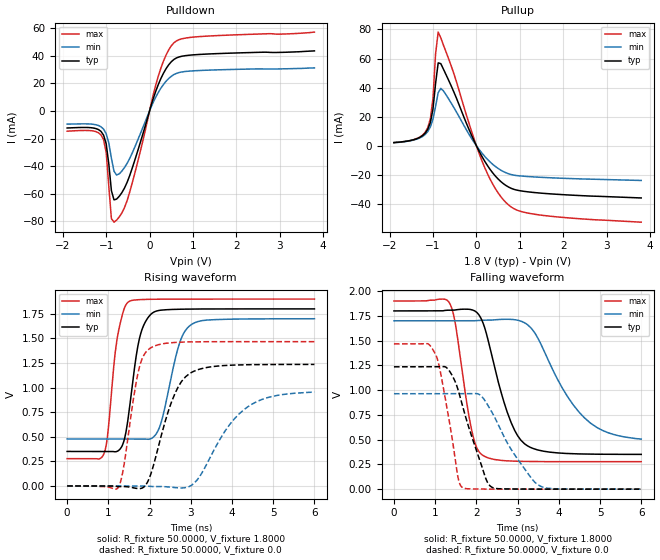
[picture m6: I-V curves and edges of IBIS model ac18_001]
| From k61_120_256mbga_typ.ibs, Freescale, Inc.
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|   Model ac18_001
[Model]  ac18_001
Model_type Output
Polarity   Non-Inverting
Enable   Active-High
Vmeas =  0.9000V
Cref =   5.0000pF
Rref =   50.0000
C_comp   2.8000pF   2.5000pF   3.3000pF
[Temperature Range]   25.0000   0.1250k   -40.0000
[Voltage Range]   1.8000V   1.7000V   1.9000V
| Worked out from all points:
|   slope of the pulldown table from 0 to 0.27 V, typ, clamps not added: 11.2 ohm
|   slope of the pullup table from 0 to 0.27 V, typ, clamps not added: 18.8 ohm
|   rising waveform, R_fixture 50.0000, V_fixture 1.8000: 20-80 % time 297ps typ, 401ps min, 243ps max; typ from 0.351 V to 1.8 V
|   rising waveform, R_fixture 50.0000, V_fixture 0.0: 20-80 % time 552ps typ, 907ps min, 324ps max; typ from 0 V to 1.24 V
|   falling waveform, R_fixture 50.0000, V_fixture 1.8000: 20-80 % time 596ps typ, 998ps min, 356ps max; typ from 1.8 V to 0.351 V
|   falling waveform, R_fixture 50.0000, V_fixture 0.0: 20-80 % time 552ps typ, 805ps min, 357ps max; typ from 1.24 V to 0 V
[Pulldown]
|Voltage   I(typ)   I(min)   I(max)
-1.9V     -12.39mA   -9.603mA   -14.7mA
-1.24V    -12.78mA   -10.03mA   -14.98mA
-1.06V    -17.59mA   -13.19mA   -20.88mA
-1V       -23.85mA   -16.51mA   -30.08mA
-880mV    -57.69mA   -34.18mA   -77.95mA
-820mV    -64.39mA   -43.65mA   -80.55mA
-700mV    -61.85mA   -45.6mA    -76.81mA
-520mV    -51.88mA   -38.09mA   -65.13mA
200mV     18.96mA    13.28mA    25.03mA
380mV     30.52mA    21.42mA    40.4mA
560mV     37.18mA    26.25mA    49.21mA
3.8V      43.4mA     31.1mA     57mA
[Pullup]
|Voltage   I(typ)   I(min)   I(max)
-1.9V     2.1mA      2.1mA      2.2mA
-1.36V    4.94mA     4.66mA     5.08mA
-1.12V    11.3mA     9.73mA     12.41mA
-1.06V    15.99mA    12.93mA    18.54mA
-1V       25.26mA    18.31mA    32.65mA
-940mV    42.87mA    27.06mA    63.32mA
-880mV    57.01mA    36.48mA    78.2mA
-760mV    52.75mA    37.76mA    69.31mA
140mV     -8.031mA   -5.52mA    -11.29mA
680mV     -27.37mA   -18.62mA   -39.09mA
1.4V      -32.43mA   -21.63mA   -47.45mA
3.8V      -35.98mA   -23.94mA   -52.67mA
[Ramp]
| variable   typ   min   max
dV/dt_r  0.7414/0.5524n   0.5724/0.9071n   0.8802/0.3244n
dV/dt_f  0.8693/0.5960n   0.7168/0.9978n   0.9734/0.3560n
R_load = 50.0000
[Rising Waveform]
R_fixture= 50.0000
V_fixture= 1.8000
V_fixture_min= 1.7000
V_fixture_max= 1.9000
|time   V(typ)   V(min)   V(max)
0s        350.9mV    477.7mV    277.6mV
902ps     350.9mV    477.7mV    337.4mV
1.21ns    351.3mV    477.7mV    1.49V
1.368ns   443.5mV    477.7mV    1.782V
1.498ns   743.7mV    477.7mV    1.875V
1.772ns   1.529V     478mV      1.895V
2.11ns    1.769V     503.5mV    1.898V
2.731ns   1.797V     1.456V     1.9V
2.996ns   1.798V     1.636V     1.9V
6ns       1.8V       1.7V       1.9V
[Rising Waveform]
R_fixture= 50.0000
V_fixture= 0.0
|time   V(typ)   V(min)   V(max)
0s        2.838nV    312.1nV    728.3pV
1.244ns   -6.3mV     729.9nV    -12.57mV
1.364ns   -5.753mV   306.7nV    173.6mV
1.745ns   -26.8mV    98.4uV     1.195V
2.052ns   148.3mV    -5.631mV   1.41V
2.537ns   859.2mV    -12.92mV   1.457V
2.947ns   1.136V     -8.28mV    1.464V
4.277ns   1.232V     771.2mV    1.467V
4.973ns   1.235V     910mV      1.467V
6ns       1.236V     954mV      1.467V
[Falling Waveform]
R_fixture= 50.0000
V_fixture= 1.8000
V_fixture_min= 1.7000
V_fixture_max= 1.9000
|time   V(typ)   V(min)   V(max)
0s        1.8V       1.7V       1.9V
1.344ns   1.807V     1.7V       1.883V
1.497ns   1.81V      1.7V       1.655V
1.907ns   1.809V     1.7V       556.3mV
2.165ns   1.675V     1.706V     339.2mV
2.746ns   780.4mV    1.716V     285.9mV
3.167ns   458.7mV    1.681V     279.9mV
3.434ns   402.7mV    1.567V     278.6mV
4.621ns   354.8mV    720.6mV    277.7mV
6ns       351.2mV    505.3mV    277.6mV
[Falling Waveform]
R_fixture= 50.0000
V_fixture= 0.0
|time   V(typ)   V(min)   V(max)
0s        1.236V     963.7mV    1.467V
813.7ps   1.236V     963.7mV    1.469V
1.008ns   1.236V     963.7mV    1.365V
1.343ns   1.195V     963.7mV    688mV
1.557ns   1.002V     963.7mV    113.1mV
1.671ns   830.9mV    963.7mV    14.3mV
2.088ns   287mV      951.8mV    1.404mV
2.395ns   15.56mV    763.8mV    542.2uV
3.517ns   405.5uV    38.29mV    16.24uV
6ns       1.818uV    122uV      -80.32nV
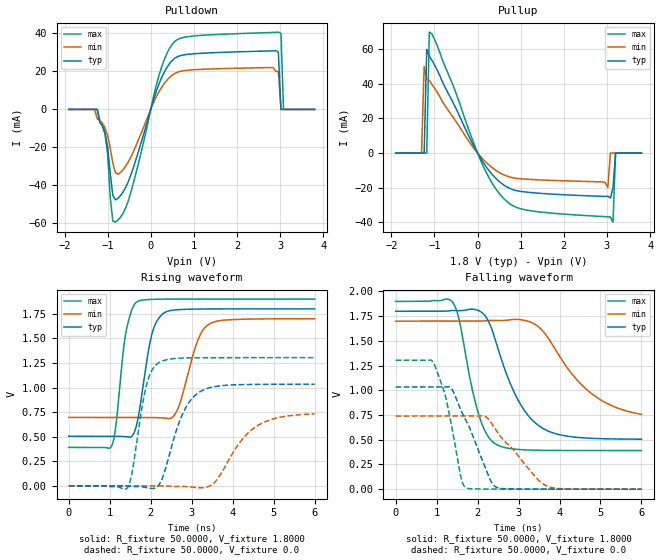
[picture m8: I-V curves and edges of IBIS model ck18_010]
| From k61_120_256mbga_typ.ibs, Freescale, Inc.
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|   Model ck18_010
[Model]  ck18_010
Model_type Output
Polarity   Non-Inverting
Enable   Active-High
Vmeas =  0.9000V
Cref =   5.0000pF
Rref =   50.0000
C_comp   2.8000pF   2.5000pF   3.3000pF
[Temperature Range]   25.0000   0.1250k   -40.0000
[Voltage Range]   1.8000V   1.7000V   1.9000V
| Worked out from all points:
|   slope of the pulldown table from 0 to 0.27 V, typ, clamps not added: 15.4 ohm
|   slope of the pullup table from 0 to 0.27 V, typ, clamps not added: 26.2 ohm
|   rising waveform, R_fixture 50.0000, V_fixture 1.8000: 20-80 % time 304ps typ, 414ps min, 240ps max; typ from 0.504 V to 1.8 V
|   rising waveform, R_fixture 50.0000, V_fixture 0.0: 20-80 % time 518ps typ, 765ps min, 316ps max; typ from 0 V to 1.03 V
|   falling waveform, R_fixture 50.0000, V_fixture 1.8000: 20-80 % time 789ps typ, 1.1ns min, 470ps max; typ from 1.8 V to 0.505 V
|   falling waveform, R_fixture 50.0000, V_fixture 0.0: 20-80 % time 632ps typ, 906ps min, 390ps max; typ from 1.03 V to 0 V
[Pulldown]
|Voltage   I(typ)   I(min)   I(max)
-1.9V     0A         0A         0A
-1.24V    0A         -5mA       0A
-1.06V    -12.26mA   -9.75mA    -13.08mA
-880mV    -45.16mA   -28.29mA   -58.8mA
-820mV    -47.6mA    -33.26mA   -59.37mA
-460mV    -34.43mA   -25.08mA   -43.58mA
260mV     17.1mA     11.87mA    22.81mA
620mV     27.74mA    19.59mA    36.79mA
2.96V     30mA       20mA       40.7mA
3.02V     0A         0A         40mA
3.08V     0A         0A         0A
3.8V      0A         0A         0A
[Pullup]
|Voltage   I(typ)   I(min)   I(max)
-1.9V     0A         0A         0A
-1.3V     0A         0A         0A
-1.24V    0A         50mA       0A
-1.18V    60mA       43mA       0A
-1.12V    56mA       42mA       70mA
140mV     -5.775mA   -3.963mA   -8.136mA
800mV     -21mA      -14.21mA   -30.2mA
3.02V     -25mA      -20mA      -36.9mA
3.08V     -26mA      0A         -37mA
3.14V     -20mA      0A         -40mA
3.2V      0A         0A         0A
3.8V      0A         0A         0A
[Ramp]
| variable   typ   min   max
dV/dt_r  0.6201/0.5176n   0.4393/0.7629n   0.7822/0.3155n
dV/dt_f  0.7768/0.7888n   0.5661/1.0989n   0.9056/0.4703n
R_load = 50.0000
[Rising Waveform]
R_fixture= 50.0000
V_fixture= 1.8000
V_fixture_min= 1.7000
V_fixture_max= 1.9000
|time   V(typ)   V(min)   V(max)
0s        504.3mV    695.5mV    390.7mV
1.053ns   504.4mV    695.5mV    413.2mV
1.39ns    501.2mV    695.5mV    1.551V
1.663ns   631.2mV    695.5mV    1.872V
2.022ns   1.532V     695.5mV    1.897V
2.319ns   1.757V     690.8mV    1.899V
2.631ns   1.791V     756.2mV    1.9V
3.134ns   1.798V     1.463V     1.9V
3.407ns   1.799V     1.64V      1.9V
6ns       1.8V       1.7V       1.9V
[Rising Waveform]
R_fixture= 50.0000
V_fixture= 0.0
|time   V(typ)   V(min)   V(max)
0s        4.987nV    391nV      2.102nV
1.434ns   -1.187mV   550.7nV    -19.32mV
1.547ns   -8.89mV    -1.382uV   140.9mV
1.897ns   -18.33mV   151.2uV    1.023V
2.222ns   23.63mV    248.5uV    1.258V
2.749ns   703.7mV    -6.341mV   1.299V
3.183ns   952.1mV    -19.63mV   1.303V
3.559ns   1.009V     33.93mV    1.303V
4.643ns   1.032V     621.2mV    1.304V
6ns       1.034V     732.1mV    1.304V
[Falling Waveform]
R_fixture= 50.0000
V_fixture= 1.8000
V_fixture_min= 1.7000
V_fixture_max= 1.9000
|time   V(typ)   V(min)   V(max)
0s        1.8V       1.7V       1.9V
1.401ns   1.808V     1.7V       1.884V
1.549ns   1.806V     1.7V       1.716V
2.02ns    1.808V     1.7V       765.4mV
2.246ns   1.714V     1.706V     539.9mV
2.437ns   1.504V     1.706V     457.3mV
2.965ns   919.8mV    1.718V     402.7mV
3.528ns   631.9mV    1.628V     393.1mV
4.65ns    517.3mV    1.013V     390.8mV
6ns       505.4mV    756.5mV    390.7mV
[Falling Waveform]
R_fixture= 50.0000
V_fixture= 0.0
|time   V(typ)   V(min)   V(max)
0s        1.034V     739.7mV    1.304V
926.6ps   1.034V     739.7mV    1.274V
1.191ns   1.034V     739.7mV    980.9mV
1.35ns    1.023V     739.7mV    670.8mV
1.601ns   790.1mV    739.7mV    106mV
1.727ns   687.2mV    739.7mV    12.69mV
2.183ns   220.8mV    737mV      1.246mV
2.481ns   15.45mV    577.3mV    483.1uV
3.71ns    322.2uV    28.09mV    15.67uV
6ns       4.302uV    159uV      344.8nV
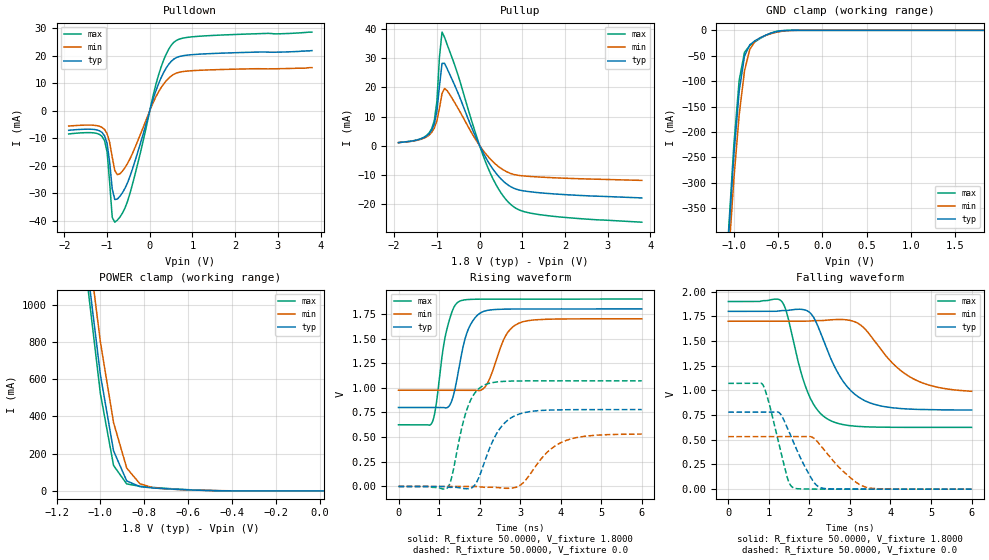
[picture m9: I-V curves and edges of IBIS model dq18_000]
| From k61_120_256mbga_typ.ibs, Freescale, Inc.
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|   Model dq18_000
[Model]  dq18_000
Model_type 3-state
Polarity   Non-Inverting
Enable   Active-High
Vmeas =  0.9000V
Cref =   5.0000pF
Rref =   50.0000
C_comp   2.8000pF   2.5000pF   3.3000pF
[Temperature Range]   25.0000   0.1250k   -40.0000
[Voltage Range]   1.8000V   1.7000V   1.9000V
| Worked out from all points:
|   slope of the pulldown table from 0 to 0.27 V, typ, clamps not added: 22.3 ohm
|   slope of the pullup table from 0 to 0.27 V, typ, clamps not added: 37.5 ohm
|   GND clamp passes 1 mA (typ) near -0.46 V on its own axis
|   POWER clamp passes 1 mA (typ) near -0.45 V on its own axis
|   rising waveform, R_fixture 50.0000, V_fixture 1.8000: 20-80 % time 328ps typ, 407ps min, 280ps max; typ from 0.801 V to 1.8 V
|   rising waveform, R_fixture 50.0000, V_fixture 0.0: 20-80 % time 529ps typ, 702ps min, 383ps max; typ from 0 V to 0.779 V
|   falling waveform, R_fixture 50.0000, V_fixture 1.8000: 20-80 % time 754ps typ, 996ps min, 547ps max; typ from 1.8 V to 0.801 V
|   falling waveform, R_fixture 50.0000, V_fixture 0.0: 20-80 % time 531ps typ, 730ps min, 379ps max; typ from 0.779 V to 0 V
[Pulldown]
|Voltage   I(typ)   I(min)   I(max)
-1.9V     -7.125mA   -5.577mA   -8.446mA
-1.3V     -6.824mA   -5.306mA   -8.077mA
-1.06V    -9.108mA   -6.813mA   -10.88mA
-1V       -11.95mA   -8.349mA   -14.97mA
-880mV    -28.41mA   -16.83mA   -38.71mA
-820mV    -32.23mA   -21.69mA   -40.45mA
-700mV    -31.06mA   -22.87mA   -38.6mA
-520mV    -26.09mA   -19.11mA   -32.8mA
200mV     9.554mA    6.678mA    12.65mA
380mV     15.35mA    10.75mA    20.37mA
560mV     18.67mA    13.17mA    24.75mA
3.8V      21.8mA     15.6mA     28.5mA
[Pullup]
|Voltage   I(typ)   I(min)   I(max)
-1.9V     1mA        1mA        1mA
-1.36V    2.37mA     2.22mA     2.46mA
-1.12V    5.32mA     4.56mA     5.88mA
-1.06V    7.48mA     6.03mA     8.69mA
-1V       11.81mA    8.57mA     15.23mA
-940mV    20.56mA    12.89mA    30.55mA
-880mV    28.3mA     17.89mA    39.08mA
-760mV    26.45mA    18.92mA    34.76mA
140mV     -4.031mA   -2.77mA    -5.668mA
680mV     -13.73mA   -9.341mA   -19.61mA
1.4V      -16.26mA   -10.85mA   -23.79mA
3.8V      -18.04mA   -12.01mA   -26.41mA
[GND_clamp]
|Voltage   I(typ)   I(min)   I(max)
-1.9V     -3.326A    -3.292A    -3.364A
-1.06V    -406.5mA   -447.4mA   -394.6mA
-1V       -245.1mA   -292.9mA   -225.5mA
-940mV    -119.4mA   -166.1mA   -98.22mA
-880mV    -50.5mA    -79.89mA   -43.13mA
-820mV    -28.4mA    -37.26mA   -29.9mA
-760mV    -20.29mA   -21.31mA   -22.38mA
-700mV    -14.5mA    -14.44mA   -15.67mA
-580mV    -5.551mA   -6.474mA   -5.066mA
-460mV    -1.018mA   -1.866mA   -602.3uA
-220mV    -979.5nA   -15.35uA   -59.46nA
1.82V     915.2pA    951.9nA    210.6pA
[POWER_clamp]
|Voltage   I(typ)   I(min)   I(max)
-1.9V     11.94A     11.89A     12.02A
-1.06V    1.204A     1.363A     1.122A
-1V       623.7mA    800mA      522.5mA
-940mV    215.1mA    367.1mA    136.6mA
-880mV    53.67mA    122.9mA    37.6mA
-820mV    23.13mA    38.48mA    24.96mA
-760mV    15.75mA    17.21mA    18.82mA
-640mV    7.758mA    7.284mA    9.105mA
-460mV    1.139mA    1.585mA    966.7uA
20mV      398.7pA    26.73nA    225pA
[Ramp]
| variable   typ   min   max
dV/dt_r  0.4676/0.5284n   0.3184/0.7023n   0.6427/0.3825n
dV/dt_f  0.5993/0.7541n   0.4255/0.9960n   0.7648/0.5470n
R_load = 50.0000
[Rising Waveform]
R_fixture= 50.0000
V_fixture= 1.8000
V_fixture_min= 1.7000
V_fixture_max= 1.9000
|time   V(typ)   V(min)   V(max)
0s        800.8mV    975.9mV    625.4mV
832.1ps   800.7mV    975.9mV    650.5mV
1.172ns   796.5mV    975.9mV    1.558V
1.322ns   877.7mV    975.9mV    1.775V
1.494ns   1.205V     975.9mV    1.876V
1.744ns   1.615V     976.1mV    1.896V
2.131ns   1.779V     1.008V     1.899V
2.62ns    1.798V     1.511V     1.9V
2.958ns   1.799V     1.653V     1.9V
6ns       1.8V       1.7V       1.9V
[Rising Waveform]
R_fixture= 50.0000
V_fixture= 0.0
|time   V(typ)   V(min)   V(max)
0s        8.256nV    861nV      2.296nV
1.216ns   -7.012mV   1.177uV    -10.98mV
1.676ns   -23.7mV    -4.494uV   768mV
1.892ns   19.47mV    69.68uV    952.6mV
2.112ns   236.5mV    -9.001mV   1.027V
2.478ns   574.3mV    -12.42mV   1.062V
2.966ns   732.3mV    3.157mV    1.07V
3.67ns    773.7mV    347.8mV    1.071V
4.109ns   777.9mV    462.5mV    1.071V
6ns       779.4mV    530.7mV    1.071V
[Falling Waveform]
R_fixture= 50.0000
V_fixture= 1.8000
V_fixture_min= 1.7000
V_fixture_max= 1.9000
|time   V(typ)   V(min)   V(max)
0s        1.8V       1.7V       1.9V
1.319ns   1.808V     1.7V       1.9V
1.455ns   1.809V     1.7V       1.765V
1.938ns   1.807V     1.7V       1V
2.149ns   1.706V     1.707V     828.8mV
2.525ns   1.325V     1.714V     692.8mV
2.926ns   1.04V      1.714V     646.8mV
3.471ns   876.9mV    1.574V     630.2mV
4.555ns   809.2mV    1.119V     625.6mV
6ns       801.2mV    990.8mV    625.4mV
[Falling Waveform]
R_fixture= 50.0000
V_fixture= 0.0
|time   V(typ)   V(min)   V(max)
0s        779.4mV    531.6mV    1.071V
852.8ps   779.4mV    531.6mV    1.056V
1.273ns   768.1mV    531.6mV    414.6mV
1.468ns   610.6mV    531.6mV    100mV
1.612ns   470.8mV    531.6mV    12.76mV
2.064ns   98.73mV    527.5mV    888.5uV
2.285ns   14.02mV    437.1mV    392.3uV
2.874ns   1.003mV    165.3mV    54.29uV
3.402ns   246.9uV    18.69mV    13.42uV
6ns       1.835uV    45.5uV     158.3nV
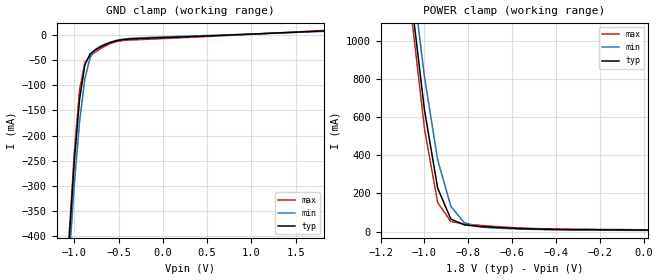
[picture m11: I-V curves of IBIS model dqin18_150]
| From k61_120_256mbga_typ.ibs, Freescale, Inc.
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|   Model dqin18_150
[Model]  dqin18_150
Model_type Input
Polarity   Non-Inverting
Enable   Active-High
Vinl =   0.6500V
Vinh =   1.1500V
C_comp   2.8000pF   2.5000pF   3.3000pF
[Temperature Range]   25.0000   0.1250k   -40.0000
[Voltage Range]   1.8000V   1.7000V   1.9000V
[GND_clamp]
|Voltage   I(typ)   I(min)   I(max)
-1.9V     -3.336A    -3.301A    -3.377A
-1.06V    -414.9mA   -454.1mA   -405mA
-1V       -253.4mA   -299.6mA   -235.9mA
-940mV    -128mA     -172.9mA   -109mA
-880mV    -59.29mA   -86.81mA   -54.27mA
-820mV    -37.29mA   -44.28mA   -41.09mA
-760mV    -29.13mA   -28.35mA   -33.51mA
-700mV    -23.28mA   -21.42mA   -26.73mA
-580mV    -14.14mA   -13.28mA   -15.95mA
-520mV    -11.13mA   -10.44mA   -12.79mA
-400mV    -8.205mA   -7.035mA   -10.22mA
1.82V     8.362mA    7.37mA     9.342mA
[POWER_clamp]
|Voltage   I(typ)   I(min)   I(max)
-1.9V     11.95A     11.89A     12.04A
-1.06V    1.217A     1.372A     1.138A
-1V       636.5mA    809.7mA    538.4mA
-940mV    227.9mA    376.9mA    152.4mA
-880mV    66.48mA    132.9mA    53.34mA
-820mV    35.86mA    48.43mA    40.57mA
-760mV    28.37mA    27.15mA    34.29mA
-640mV    20.08mA    17.06mA    24.21mA
-460mV    12.76mA    10.86mA    15.22mA
20mV      8.048mA    6.473mA    9.907mA
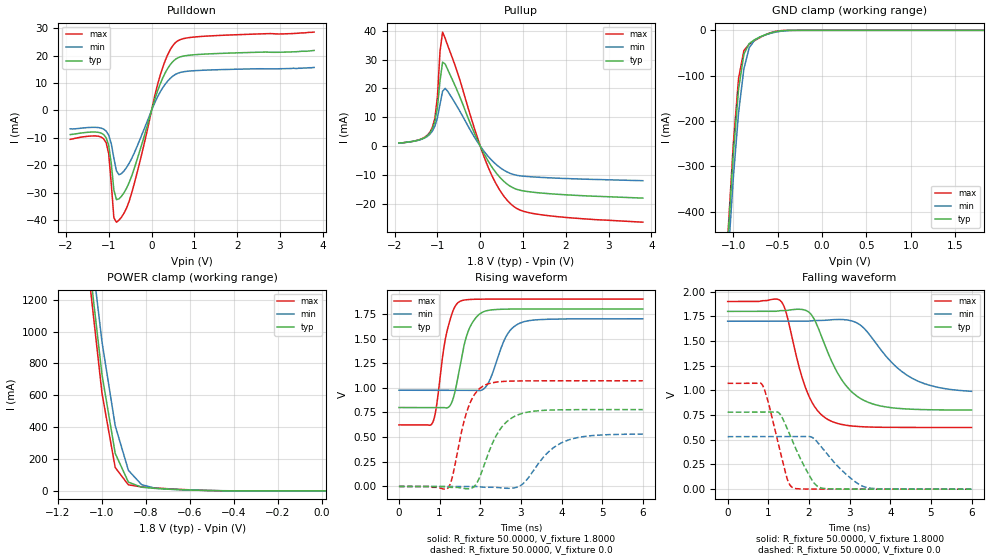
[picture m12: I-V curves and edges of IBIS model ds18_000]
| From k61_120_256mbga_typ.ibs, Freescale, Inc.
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|   Model ds18_000
[Model]  ds18_000
Model_type 3-state
Polarity   Non-Inverting
Enable   Active-High
Vmeas =  0.9000V
Cref =   5.0000pF
Rref =   50.0000
C_comp   2.8000pF   2.5000pF   3.3000pF
[Temperature Range]   25.0000   0.1250k   -40.0000
[Voltage Range]   1.8000V   1.7000V   1.9000V
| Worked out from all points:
|   slope of the pulldown table from 0 to 0.27 V, typ, clamps not added: 22.3 ohm
|   slope of the pullup table from 0 to 0.27 V, typ, clamps not added: 37.5 ohm
|   GND clamp passes 1 mA (typ) near -0.46 V on its own axis
|   POWER clamp passes 1 mA (typ) near -0.45 V on its own axis
|   rising waveform, R_fixture 50.0000, V_fixture 1.8000: 20-80 % time 330ps typ, 409ps min, 281ps max; typ from 0.8 V to 1.8 V
|   rising waveform, R_fixture 50.0000, V_fixture 0.0: 20-80 % time 529ps typ, 704ps min, 384ps max; typ from 0 V to 0.779 V
|   falling waveform, R_fixture 50.0000, V_fixture 1.8000: 20-80 % time 757ps typ, 997ps min, 549ps max; typ from 1.8 V to 0.801 V
|   falling waveform, R_fixture 50.0000, V_fixture 0.0: 20-80 % time 531ps typ, 731ps min, 380ps max; typ from 0.78 V to 0 V
[Pulldown]
|Voltage   I(typ)   I(min)   I(max)
-1.9V     -8.795mA   -6.718mA   -10.56mA
-1.3V     -7.878mA   -6.162mA   -9.3mA
-1.06V    -9.952mA   -7.517mA   -11.8mA
-1V       -12.77mA   -9.023mA   -15.84mA
-880mV    -28.98mA   -17.42mA   -39.16mA
-820mV    -32.52mA   -22.06mA   -40.76mA
-700mV    -31.25mA   -23mA      -38.87mA
-520mV    -26.21mA   -19.19mA   -32.98mA
200mV     9.585mA    6.693mA    12.71mA
380mV     15.39mA    10.77mA    20.43mA
560mV     18.7mA     13.18mA    24.78mA
3.8V      21.9mA     15.7mA     28.6mA
[Pullup]
|Voltage   I(typ)   I(min)   I(max)
-1.9V     1.1mA      1mA        1.1mA
-1.36V    2.54mA     2.42mA     2.59mA
-1.12V    5.91mA     5.16mA     6.42mA
-1.06V    8.46mA     6.91mA     9.69mA
-1V       13.48mA    9.86mA     17.21mA
-940mV    22.68mA    14.53mA    32.91mA
-880mV    29.13mA    19.06mA    39.59mA
-760mV    26.56mA    19.04mA    34.92mA
140mV     -4.036mA   -2.773mA   -5.677mA
680mV     -13.74mA   -9.344mA   -19.62mA
1.4V      -16.26mA   -10.85mA   -23.79mA
3.8V      -18.06mA   -12.02mA   -26.42mA
[GND_clamp]
|Voltage   I(typ)   I(min)   I(max)
-1.9V     -3.878A    -3.837A    -3.924A
-1.06V    -463.9mA   -508.9mA   -451.7mA
-1V       -275.3mA   -328.7mA   -253.8mA
-940mV    -130mA     -182.2mA   -106.3mA
-880mV    -52.76mA   -84.89mA   -44.65mA
-820mV    -29.19mA   -38.6mA    -30.71mA
-760mV    -20.79mA   -21.86mA   -22.97mA
-700mV    -14.85mA   -14.77mA   -16.07mA
-580mV    -5.674mA   -6.612mA   -5.186mA
-460mV    -1.038mA   -1.902mA   -615.1uA
-220mV    -1.001uA   -15.63uA   -61.01nA
1.82V     927pA      961.6nA    217.2pA
[POWER_clamp]
|Voltage   I(typ)   I(min)   I(max)
-1.9V     14.99A     14.89A     15.1A
-1.06V    1.452A     1.634A     1.361A
-1V       729.6mA    935mA      612.3mA
-940mV    235.7mA    409.7mA    146.8mA
-880mV    55.12mA    129.3mA    38.22mA
-820mV    23.43mA    39.21mA    25.26mA
-760mV    15.93mA    17.42mA    19.04mA
-640mV    7.842mA    7.36mA     9.207mA
-460mV    1.151mA    1.601mA    977.3uA
20mV      403.6pA    26.53nA    232.4pA
[Ramp]
| variable   typ   min   max
dV/dt_r  0.4677/0.5294n   0.3184/0.7036n   0.6428/0.3840n
dV/dt_f  0.5996/0.7568n   0.4256/0.9970n   0.7654/0.5487n
R_load = 50.0000
[Rising Waveform]
R_fixture= 50.0000
V_fixture= 1.8000
V_fixture_min= 1.7000
V_fixture_max= 1.9000
|time   V(typ)   V(min)   V(max)
0s        800.3mV    975.6mV    624.4mV
831.1ps   800.2mV    975.6mV    648.7mV
1.167ns   796mV      975.6mV    1.546V
1.329ns   885.2mV    975.6mV    1.78V
1.493ns   1.201V     975.6mV    1.875V
1.727ns   1.597V     975.7mV    1.896V
2.114ns   1.777V     999.5mV    1.899V
2.641ns   1.798V     1.525V     1.9V
2.967ns   1.799V     1.654V     1.9V
6ns       1.8V       1.7V       1.9V
[Rising Waveform]
R_fixture= 50.0000
V_fixture= 0.0
|time   V(typ)   V(min)   V(max)
0s        8.563nV    880.7nV    2.443nV
1.211ns   -6.621mV   1.219uV    -13.57mV
1.321ns   -8.717mV   1.206uV    107.9mV
1.685ns   -23.66mV   776.3nV    777.2mV
1.9ns     23.53mV    -104.4uV   955.4mV
2.135ns   261.9mV    -9.105mV   1.031V
2.524ns   599.4mV    -14.38mV   1.064V
3.008ns   737.9mV    13.59mV    1.07V
4.078ns   777.7mV    457mV      1.071V
6ns       779.4mV    530.7mV    1.071V
[Falling Waveform]
R_fixture= 50.0000
V_fixture= 1.8000
V_fixture_min= 1.7000
V_fixture_max= 1.9000
|time   V(typ)   V(min)   V(max)
0s        1.8V       1.7V       1.9V
1.309ns   1.808V     1.7V       1.904V
1.445ns   1.808V     1.7V       1.779V
1.932ns   1.808V     1.7V       1.008V
2.158ns   1.698V     1.707V     824.2mV
2.524ns   1.327V     1.714V     692.8mV
2.979ns   1.016V     1.71V      643.3mV
3.544ns   866mV      1.535V     628.4mV
4.558ns   808.8mV    1.118V     624.7mV
6ns       800.7mV    990.6mV    624.4mV
[Falling Waveform]
R_fixture= 50.0000
V_fixture= 0.0
|time   V(typ)   V(min)   V(max)
0s        779.5mV    531.6mV    1.071V
854.9ps   779.5mV    531.6mV    1.055V
1.273ns   768.1mV    531.6mV    415.6mV
1.48ns    600mV      531.6mV    86.19mV
1.608ns   475.2mV    531.6mV    13.59mV
2.07ns    95.99mV    526.5mV    868.3uV
2.298ns   12.6mV     430.8mV    371.7uV
2.876ns   991.1uV    165.1mV    52.31uV
3.387ns   257.1uV    20.73mV    14.05uV
6ns       1.703uV    44.82uV    96.66nV
